VERSION 5.7 ;
  NOWIREEXTENSIONATPIN ON ;
  DIVIDERCHAR "/" ;
  BUSBITCHARS "[]" ;
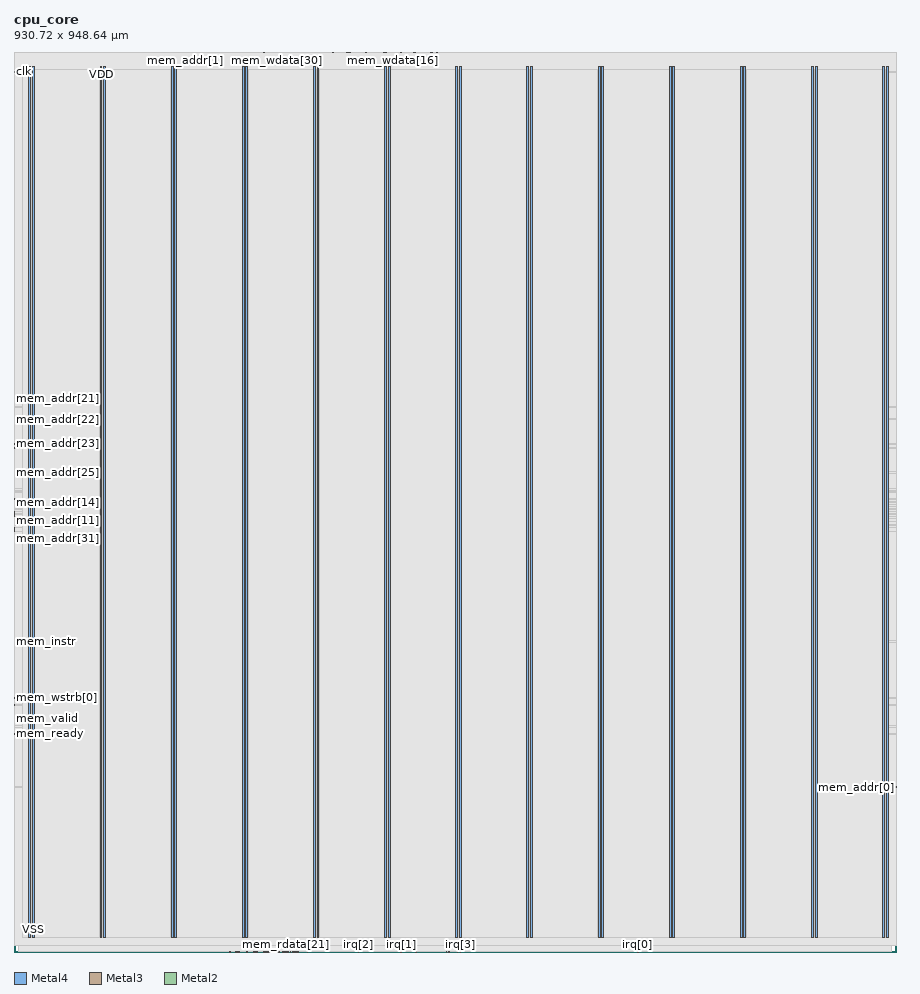
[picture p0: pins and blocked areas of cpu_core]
MACRO cpu_core
  CLASS BLOCK ;
  FOREIGN cpu_core ;
  ORIGIN 0.000 0.000 ;
  SIZE 930.720 BY 948.640 ;
  PIN VDD
    DIRECTION INOUT ;
    USE POWER ;
    PORT
      LAYER Metal4 ;
        RECT 15.720 15.380 17.720 933.260 ;
    END
    PORT
      LAYER Metal4 ;
        RECT 90.720 15.380 92.720 933.260 ;
    END
    PORT
      LAYER Metal4 ;
        RECT 165.720 15.380 167.720 933.260 ;
    END
    PORT
      LAYER Metal4 ;
        RECT 240.720 15.380 242.720 933.260 ;
    END
    PORT
      LAYER Metal4 ;
        RECT 315.720 15.380 317.720 933.260 ;
    END
    PORT
      LAYER Metal4 ;
        RECT 390.720 15.380 392.720 933.260 ;
    END
    PORT
      LAYER Metal4 ;
        RECT 465.720 15.380 467.720 933.260 ;
    END
    PORT
      LAYER Metal4 ;
        RECT 540.720 15.380 542.720 933.260 ;
    END
    PORT
      LAYER Metal4 ;
        RECT 615.720 15.380 617.720 933.260 ;
    END
    PORT
      LAYER Metal4 ;
        RECT 690.720 15.380 692.720 933.260 ;
    END
    PORT
      LAYER Metal4 ;
        RECT 765.720 15.380 767.720 933.260 ;
    END
    PORT
      LAYER Metal4 ;
        RECT 840.720 15.380 842.720 933.260 ;
    END
    PORT
      LAYER Metal4 ;
        RECT 915.720 15.380 917.720 933.260 ;
    END
  END VDD
  PIN VSS
    DIRECTION INOUT ;
    USE GROUND ;
    PORT
      LAYER Metal4 ;
        RECT 19.420 15.380 21.420 933.260 ;
    END
    PORT
      LAYER Metal4 ;
        RECT 94.420 15.380 96.420 933.260 ;
    END
    PORT
      LAYER Metal4 ;
        RECT 169.420 15.380 171.420 933.260 ;
    END
    PORT
      LAYER Metal4 ;
        RECT 244.420 15.380 246.420 933.260 ;
    END
    PORT
      LAYER Metal4 ;
        RECT 319.420 15.380 321.420 933.260 ;
    END
    PORT
      LAYER Metal4 ;
        RECT 394.420 15.380 396.420 933.260 ;
    END
    PORT
      LAYER Metal4 ;
        RECT 469.420 15.380 471.420 933.260 ;
    END
    PORT
      LAYER Metal4 ;
        RECT 544.420 15.380 546.420 933.260 ;
    END
    PORT
      LAYER Metal4 ;
        RECT 619.420 15.380 621.420 933.260 ;
    END
    PORT
      LAYER Metal4 ;
        RECT 694.420 15.380 696.420 933.260 ;
    END
    PORT
      LAYER Metal4 ;
        RECT 769.420 15.380 771.420 933.260 ;
    END
    PORT
      LAYER Metal4 ;
        RECT 844.420 15.380 846.420 933.260 ;
    END
    PORT
      LAYER Metal4 ;
        RECT 919.420 15.380 921.420 933.260 ;
    END
  END VSS
  PIN clk
    DIRECTION INPUT ;
    USE SIGNAL ;
    ANTENNAGATEAREA 4.738000 ;
    PORT
      LAYER Metal3 ;
        RECT 0.000 927.360 0.560 927.920 ;
    END
  END clk
  PIN irq[0]
    DIRECTION INPUT ;
    USE SIGNAL ;
    ANTENNAGATEAREA 0.498500 ;
    PORT
      LAYER Metal2 ;
        RECT 657.440 0.000 658.000 0.560 ;
    END
  END irq[0]
  PIN irq[1]
    DIRECTION INPUT ;
    USE SIGNAL ;
    ANTENNAGATEAREA 0.498500 ;
    PORT
      LAYER Metal2 ;
        RECT 407.680 0.000 408.240 0.560 ;
    END
  END irq[1]
  PIN irq[2]
    DIRECTION INPUT ;
    USE SIGNAL ;
    ANTENNAGATEAREA 0.498500 ;
    PORT
      LAYER Metal2 ;
        RECT 362.880 0.000 363.440 0.560 ;
    END
  END irq[2]
  PIN irq[3]
    DIRECTION INPUT ;
    USE SIGNAL ;
    ANTENNAGATEAREA 0.498500 ;
    PORT
      LAYER Metal2 ;
        RECT 470.400 0.000 470.960 0.560 ;
    END
  END irq[3]
  PIN irq[4]
    DIRECTION INPUT ;
    USE SIGNAL ;
    ANTENNAGATEAREA 0.498500 ;
    PORT
      LAYER Metal2 ;
        RECT 455.840 0.000 456.400 0.560 ;
    END
  END irq[4]
  PIN irq[5]
    DIRECTION INPUT ;
    USE SIGNAL ;
    ANTENNAGATEAREA 0.498500 ;
    PORT
      LAYER Metal2 ;
        RECT 458.080 0.000 458.640 0.560 ;
    END
  END irq[5]
  PIN irq[6]
    DIRECTION INPUT ;
    USE SIGNAL ;
    ANTENNAGATEAREA 0.498500 ;
    PORT
      LAYER Metal2 ;
        RECT 423.360 0.000 423.920 0.560 ;
    END
  END irq[6]
  PIN irq[7]
    DIRECTION INPUT ;
    USE SIGNAL ;
    ANTENNAGATEAREA 0.498500 ;
    PORT
      LAYER Metal2 ;
        RECT 467.040 0.000 467.600 0.560 ;
    END
  END irq[7]
  PIN mem_addr[0]
    DIRECTION OUTPUT ;
    USE SIGNAL ;
    ANTENNADIFFAREA 0.360800 ;
    PORT
      LAYER Metal3 ;
        RECT 930.160 173.600 930.720 174.160 ;
    END
  END mem_addr[0]
  PIN mem_addr[10]
    DIRECTION OUTPUT ;
    USE SIGNAL ;
    ANTENNADIFFAREA 1.986000 ;
    PORT
      LAYER Metal3 ;
        RECT 0.000 459.200 0.560 459.760 ;
    END
  END mem_addr[10]
  PIN mem_addr[11]
    DIRECTION OUTPUT ;
    USE SIGNAL ;
    ANTENNADIFFAREA 1.986000 ;
    PORT
      LAYER Metal3 ;
        RECT 0.000 454.720 0.560 455.280 ;
    END
  END mem_addr[11]
  PIN mem_addr[12]
    DIRECTION OUTPUT ;
    USE SIGNAL ;
    ANTENNADIFFAREA 1.986000 ;
    PORT
      LAYER Metal2 ;
        RECT 436.800 948.080 437.360 948.640 ;
    END
  END mem_addr[12]
  PIN mem_addr[13]
    DIRECTION OUTPUT ;
    USE SIGNAL ;
    ANTENNADIFFAREA 1.986000 ;
    PORT
      LAYER Metal2 ;
        RECT 432.320 948.080 432.880 948.640 ;
    END
  END mem_addr[13]
  PIN mem_addr[14]
    DIRECTION OUTPUT ;
    USE SIGNAL ;
    ANTENNADIFFAREA 1.986000 ;
    PORT
      LAYER Metal3 ;
        RECT 0.000 473.760 0.560 474.320 ;
    END
  END mem_addr[14]
  PIN mem_addr[15]
    DIRECTION OUTPUT ;
    USE SIGNAL ;
    ANTENNADIFFAREA 1.986000 ;
    PORT
      LAYER Metal2 ;
        RECT 416.640 948.080 417.200 948.640 ;
    END
  END mem_addr[15]
  PIN mem_addr[16]
    DIRECTION OUTPUT ;
    USE SIGNAL ;
    ANTENNADIFFAREA 1.986000 ;
    PORT
      LAYER Metal2 ;
        RECT 421.120 948.080 421.680 948.640 ;
    END
  END mem_addr[16]
  PIN mem_addr[17]
    DIRECTION OUTPUT ;
    USE SIGNAL ;
    ANTENNADIFFAREA 1.986000 ;
    PORT
      LAYER Metal2 ;
        RECT 407.680 948.080 408.240 948.640 ;
    END
  END mem_addr[17]
  PIN mem_addr[18]
    DIRECTION OUTPUT ;
    USE SIGNAL ;
    ANTENNADIFFAREA 1.986000 ;
    PORT
      LAYER Metal3 ;
        RECT 0.000 477.120 0.560 477.680 ;
    END
  END mem_addr[18]
  PIN mem_addr[19]
    DIRECTION OUTPUT ;
    USE SIGNAL ;
    ANTENNADIFFAREA 1.986000 ;
    PORT
      LAYER Metal2 ;
        RECT 440.160 948.080 440.720 948.640 ;
    END
  END mem_addr[19]
  PIN mem_addr[1]
    DIRECTION OUTPUT ;
    USE SIGNAL ;
    ANTENNADIFFAREA 0.360800 ;
    PORT
      LAYER Metal2 ;
        RECT 180.320 948.080 180.880 948.640 ;
    END
  END mem_addr[1]
  PIN mem_addr[20]
    DIRECTION OUTPUT ;
    USE SIGNAL ;
    ANTENNADIFFAREA 1.986000 ;
    PORT
      LAYER Metal2 ;
        RECT 417.760 948.080 418.320 948.640 ;
    END
  END mem_addr[20]
  PIN mem_addr[21]
    DIRECTION OUTPUT ;
    USE SIGNAL ;
    ANTENNADIFFAREA 1.986000 ;
    PORT
      LAYER Metal3 ;
        RECT 0.000 574.560 0.560 575.120 ;
    END
  END mem_addr[21]
  PIN mem_addr[22]
    DIRECTION OUTPUT ;
    USE SIGNAL ;
    ANTENNADIFFAREA 1.986000 ;
    PORT
      LAYER Metal3 ;
        RECT 0.000 561.120 0.560 561.680 ;
    END
  END mem_addr[22]
  PIN mem_addr[23]
    DIRECTION OUTPUT ;
    USE SIGNAL ;
    ANTENNADIFFAREA 1.986000 ;
    PORT
      LAYER Metal3 ;
        RECT 0.000 535.360 0.560 535.920 ;
    END
  END mem_addr[23]
  PIN mem_addr[24]
    DIRECTION OUTPUT ;
    USE SIGNAL ;
    ANTENNADIFFAREA 1.986000 ;
    PORT
      LAYER Metal3 ;
        RECT 0.000 530.880 0.560 531.440 ;
    END
  END mem_addr[24]
  PIN mem_addr[25]
    DIRECTION OUTPUT ;
    USE SIGNAL ;
    ANTENNADIFFAREA 1.986000 ;
    PORT
      LAYER Metal3 ;
        RECT 0.000 505.120 0.560 505.680 ;
    END
  END mem_addr[25]
  PIN mem_addr[26]
    DIRECTION OUTPUT ;
    USE SIGNAL ;
    ANTENNADIFFAREA 1.986000 ;
    PORT
      LAYER Metal3 ;
        RECT 0.000 484.960 0.560 485.520 ;
    END
  END mem_addr[26]
  PIN mem_addr[27]
    DIRECTION OUTPUT ;
    USE SIGNAL ;
    ANTENNADIFFAREA 1.986000 ;
    PORT
      LAYER Metal3 ;
        RECT 0.000 487.200 0.560 487.760 ;
    END
  END mem_addr[27]
  PIN mem_addr[28]
    DIRECTION OUTPUT ;
    USE SIGNAL ;
    ANTENNADIFFAREA 1.986000 ;
    PORT
      LAYER Metal3 ;
        RECT 0.000 463.680 0.560 464.240 ;
    END
  END mem_addr[28]
  PIN mem_addr[29]
    DIRECTION OUTPUT ;
    USE SIGNAL ;
    ANTENNADIFFAREA 1.986000 ;
    PORT
      LAYER Metal3 ;
        RECT 0.000 462.560 0.560 463.120 ;
    END
  END mem_addr[29]
  PIN mem_addr[2]
    DIRECTION OUTPUT ;
    USE SIGNAL ;
    ANTENNADIFFAREA 1.986000 ;
    PORT
      LAYER Metal3 ;
        RECT 0.000 467.040 0.560 467.600 ;
    END
  END mem_addr[2]
  PIN mem_addr[30]
    DIRECTION OUTPUT ;
    USE SIGNAL ;
    ANTENNADIFFAREA 1.986000 ;
    PORT
      LAYER Metal3 ;
        RECT 0.000 453.600 0.560 454.160 ;
    END
  END mem_addr[30]
  PIN mem_addr[31]
    DIRECTION OUTPUT ;
    USE SIGNAL ;
    ANTENNADIFFAREA 1.986000 ;
    PORT
      LAYER Metal3 ;
        RECT 0.000 443.520 0.560 444.080 ;
    END
  END mem_addr[31]
  PIN mem_addr[3]
    DIRECTION OUTPUT ;
    USE SIGNAL ;
    ANTENNADIFFAREA 1.986000 ;
    PORT
      LAYER Metal3 ;
        RECT 0.000 444.640 0.560 445.200 ;
    END
  END mem_addr[3]
  PIN mem_addr[4]
    DIRECTION OUTPUT ;
    USE SIGNAL ;
    ANTENNADIFFAREA 1.986000 ;
    PORT
      LAYER Metal3 ;
        RECT 0.000 460.320 0.560 460.880 ;
    END
  END mem_addr[4]
  PIN mem_addr[5]
    DIRECTION OUTPUT ;
    USE SIGNAL ;
    ANTENNADIFFAREA 1.986000 ;
    PORT
      LAYER Metal3 ;
        RECT 0.000 446.880 0.560 447.440 ;
    END
  END mem_addr[5]
  PIN mem_addr[6]
    DIRECTION OUTPUT ;
    USE SIGNAL ;
    ANTENNADIFFAREA 1.986000 ;
    PORT
      LAYER Metal3 ;
        RECT 0.000 470.400 0.560 470.960 ;
    END
  END mem_addr[6]
  PIN mem_addr[7]
    DIRECTION OUTPUT ;
    USE SIGNAL ;
    ANTENNADIFFAREA 1.986000 ;
    PORT
      LAYER Metal3 ;
        RECT 0.000 450.240 0.560 450.800 ;
    END
  END mem_addr[7]
  PIN mem_addr[8]
    DIRECTION OUTPUT ;
    USE SIGNAL ;
    ANTENNADIFFAREA 1.986000 ;
    PORT
      LAYER Metal3 ;
        RECT 0.000 455.840 0.560 456.400 ;
    END
  END mem_addr[8]
  PIN mem_addr[9]
    DIRECTION OUTPUT ;
    USE SIGNAL ;
    ANTENNADIFFAREA 1.986000 ;
    PORT
      LAYER Metal3 ;
        RECT 0.000 445.760 0.560 446.320 ;
    END
  END mem_addr[9]
  PIN mem_instr
    DIRECTION OUTPUT ;
    USE SIGNAL ;
    ANTENNADIFFAREA 1.986000 ;
    PORT
      LAYER Metal3 ;
        RECT 0.000 327.040 0.560 327.600 ;
    END
  END mem_instr
  PIN mem_rdata[0]
    DIRECTION INPUT ;
    USE SIGNAL ;
    ANTENNAGATEAREA 0.498500 ;
    PORT
      LAYER Metal2 ;
        RECT 235.200 0.000 235.760 0.560 ;
    END
  END mem_rdata[0]
  PIN mem_rdata[10]
    DIRECTION INPUT ;
    USE SIGNAL ;
    ANTENNAGATEAREA 0.498500 ;
    PORT
      LAYER Metal2 ;
        RECT 284.480 0.000 285.040 0.560 ;
    END
  END mem_rdata[10]
  PIN mem_rdata[11]
    DIRECTION INPUT ;
    USE SIGNAL ;
    ANTENNAGATEAREA 0.498500 ;
    PORT
      LAYER Metal2 ;
        RECT 285.600 0.000 286.160 0.560 ;
    END
  END mem_rdata[11]
  PIN mem_rdata[12]
    DIRECTION INPUT ;
    USE SIGNAL ;
    ANTENNAGATEAREA 0.498500 ;
    PORT
      LAYER Metal2 ;
        RECT 227.360 0.000 227.920 0.560 ;
    END
  END mem_rdata[12]
  PIN mem_rdata[13]
    DIRECTION INPUT ;
    USE SIGNAL ;
    ANTENNAGATEAREA 0.498500 ;
    PORT
      LAYER Metal2 ;
        RECT 253.120 0.000 253.680 0.560 ;
    END
  END mem_rdata[13]
  PIN mem_rdata[14]
    DIRECTION INPUT ;
    USE SIGNAL ;
    ANTENNAGATEAREA 0.498500 ;
    PORT
      LAYER Metal2 ;
        RECT 245.280 0.000 245.840 0.560 ;
    END
  END mem_rdata[14]
  PIN mem_rdata[15]
    DIRECTION INPUT ;
    USE SIGNAL ;
    ANTENNAGATEAREA 0.498500 ;
    PORT
      LAYER Metal2 ;
        RECT 283.360 0.000 283.920 0.560 ;
    END
  END mem_rdata[15]
  PIN mem_rdata[16]
    DIRECTION INPUT ;
    USE SIGNAL ;
    ANTENNAGATEAREA 0.498500 ;
    PORT
      LAYER Metal2 ;
        RECT 254.240 0.000 254.800 0.560 ;
    END
  END mem_rdata[16]
  PIN mem_rdata[17]
    DIRECTION INPUT ;
    USE SIGNAL ;
    ANTENNAGATEAREA 0.498500 ;
    PORT
      LAYER Metal2 ;
        RECT 274.400 0.000 274.960 0.560 ;
    END
  END mem_rdata[17]
  PIN mem_rdata[18]
    DIRECTION INPUT ;
    USE SIGNAL ;
    ANTENNAGATEAREA 0.498500 ;
    PORT
      LAYER Metal2 ;
        RECT 293.440 0.000 294.000 0.560 ;
    END
  END mem_rdata[18]
  PIN mem_rdata[19]
    DIRECTION INPUT ;
    USE SIGNAL ;
    ANTENNAGATEAREA 0.498500 ;
    PORT
      LAYER Metal2 ;
        RECT 263.200 0.000 263.760 0.560 ;
    END
  END mem_rdata[19]
  PIN mem_rdata[1]
    DIRECTION INPUT ;
    USE SIGNAL ;
    ANTENNAGATEAREA 0.498500 ;
    PORT
      LAYER Metal2 ;
        RECT 265.440 0.000 266.000 0.560 ;
    END
  END mem_rdata[1]
  PIN mem_rdata[20]
    DIRECTION INPUT ;
    USE SIGNAL ;
    ANTENNAGATEAREA 0.498500 ;
    PORT
      LAYER Metal2 ;
        RECT 276.640 0.000 277.200 0.560 ;
    END
  END mem_rdata[20]
  PIN mem_rdata[21]
    DIRECTION INPUT ;
    USE SIGNAL ;
    ANTENNAGATEAREA 0.498500 ;
    PORT
      LAYER Metal2 ;
        RECT 286.720 0.000 287.280 0.560 ;
    END
  END mem_rdata[21]
  PIN mem_rdata[22]
    DIRECTION INPUT ;
    USE SIGNAL ;
    ANTENNAGATEAREA 0.498500 ;
    PORT
      LAYER Metal2 ;
        RECT 275.520 0.000 276.080 0.560 ;
    END
  END mem_rdata[22]
  PIN mem_rdata[23]
    DIRECTION INPUT ;
    USE SIGNAL ;
    ANTENNAGATEAREA 0.498500 ;
    PORT
      LAYER Metal2 ;
        RECT 294.560 0.000 295.120 0.560 ;
    END
  END mem_rdata[23]
  PIN mem_rdata[24]
    DIRECTION INPUT ;
    USE SIGNAL ;
    ANTENNAGATEAREA 0.498500 ;
    PORT
      LAYER Metal2 ;
        RECT 299.040 0.000 299.600 0.560 ;
    END
  END mem_rdata[24]
  PIN mem_rdata[25]
    DIRECTION INPUT ;
    USE SIGNAL ;
    ANTENNAGATEAREA 0.498500 ;
    PORT
      LAYER Metal2 ;
        RECT 295.680 0.000 296.240 0.560 ;
    END
  END mem_rdata[25]
  PIN mem_rdata[26]
    DIRECTION INPUT ;
    USE SIGNAL ;
    ANTENNAGATEAREA 0.498500 ;
    PORT
      LAYER Metal2 ;
        RECT 273.280 0.000 273.840 0.560 ;
    END
  END mem_rdata[26]
  PIN mem_rdata[27]
    DIRECTION INPUT ;
    USE SIGNAL ;
    ANTENNAGATEAREA 0.498500 ;
    PORT
      LAYER Metal2 ;
        RECT 236.320 0.000 236.880 0.560 ;
    END
  END mem_rdata[27]
  PIN mem_rdata[28]
    DIRECTION INPUT ;
    USE SIGNAL ;
    ANTENNAGATEAREA 0.498500 ;
    PORT
      LAYER Metal2 ;
        RECT 232.960 0.000 233.520 0.560 ;
    END
  END mem_rdata[28]
  PIN mem_rdata[29]
    DIRECTION INPUT ;
    USE SIGNAL ;
    ANTENNAGATEAREA 0.498500 ;
    PORT
      LAYER Metal2 ;
        RECT 255.360 0.000 255.920 0.560 ;
    END
  END mem_rdata[29]
  PIN mem_rdata[2]
    DIRECTION INPUT ;
    USE SIGNAL ;
    ANTENNAGATEAREA 0.498500 ;
    PORT
      LAYER Metal2 ;
        RECT 287.840 0.000 288.400 0.560 ;
    END
  END mem_rdata[2]
  PIN mem_rdata[30]
    DIRECTION INPUT ;
    USE SIGNAL ;
    ANTENNAGATEAREA 0.498500 ;
    PORT
      LAYER Metal2 ;
        RECT 234.080 0.000 234.640 0.560 ;
    END
  END mem_rdata[30]
  PIN mem_rdata[31]
    DIRECTION INPUT ;
    USE SIGNAL ;
    ANTENNAGATEAREA 0.498500 ;
    PORT
      LAYER Metal2 ;
        RECT 237.440 0.000 238.000 0.560 ;
    END
  END mem_rdata[31]
  PIN mem_rdata[3]
    DIRECTION INPUT ;
    USE SIGNAL ;
    ANTENNAGATEAREA 0.498500 ;
    PORT
      LAYER Metal2 ;
        RECT 264.320 0.000 264.880 0.560 ;
    END
  END mem_rdata[3]
  PIN mem_rdata[4]
    DIRECTION INPUT ;
    USE SIGNAL ;
    ANTENNAGATEAREA 0.498500 ;
    PORT
      LAYER Metal2 ;
        RECT 266.560 0.000 267.120 0.560 ;
    END
  END mem_rdata[4]
  PIN mem_rdata[5]
    DIRECTION INPUT ;
    USE SIGNAL ;
    ANTENNAGATEAREA 0.498500 ;
    PORT
      LAYER Metal2 ;
        RECT 291.200 0.000 291.760 0.560 ;
    END
  END mem_rdata[5]
  PIN mem_rdata[6]
    DIRECTION INPUT ;
    USE SIGNAL ;
    ANTENNAGATEAREA 0.498500 ;
    PORT
      LAYER Metal2 ;
        RECT 267.680 0.000 268.240 0.560 ;
    END
  END mem_rdata[6]
  PIN mem_rdata[7]
    DIRECTION INPUT ;
    USE SIGNAL ;
    ANTENNAGATEAREA 0.498500 ;
    PORT
      LAYER Metal2 ;
        RECT 288.960 0.000 289.520 0.560 ;
    END
  END mem_rdata[7]
  PIN mem_rdata[8]
    DIRECTION INPUT ;
    USE SIGNAL ;
    ANTENNAGATEAREA 0.498500 ;
    PORT
      LAYER Metal2 ;
        RECT 296.800 0.000 297.360 0.560 ;
    END
  END mem_rdata[8]
  PIN mem_rdata[9]
    DIRECTION INPUT ;
    USE SIGNAL ;
    ANTENNAGATEAREA 0.498500 ;
    PORT
      LAYER Metal2 ;
        RECT 278.880 0.000 279.440 0.560 ;
    END
  END mem_rdata[9]
  PIN mem_ready
    DIRECTION INPUT ;
    USE SIGNAL ;
    ANTENNAGATEAREA 0.498500 ;
    PORT
      LAYER Metal3 ;
        RECT 0.000 229.600 0.560 230.160 ;
    END
  END mem_ready
  PIN mem_valid
    DIRECTION OUTPUT ;
    USE SIGNAL ;
    ANTENNADIFFAREA 1.986000 ;
    PORT
      LAYER Metal3 ;
        RECT 0.000 237.440 0.560 238.000 ;
    END
  END mem_valid
  PIN mem_wdata[0]
    DIRECTION OUTPUT ;
    USE SIGNAL ;
    ANTENNADIFFAREA 1.986000 ;
    PORT
      LAYER Metal2 ;
        RECT 439.040 948.080 439.600 948.640 ;
    END
  END mem_wdata[0]
  PIN mem_wdata[10]
    DIRECTION OUTPUT ;
    USE SIGNAL ;
    ANTENNADIFFAREA 1.986000 ;
    PORT
      LAYER Metal2 ;
        RECT 361.760 948.080 362.320 948.640 ;
    END
  END mem_wdata[10]
  PIN mem_wdata[11]
    DIRECTION OUTPUT ;
    USE SIGNAL ;
    ANTENNADIFFAREA 1.986000 ;
    PORT
      LAYER Metal2 ;
        RECT 392.000 948.080 392.560 948.640 ;
    END
  END mem_wdata[11]
  PIN mem_wdata[12]
    DIRECTION OUTPUT ;
    USE SIGNAL ;
    ANTENNADIFFAREA 1.986000 ;
    PORT
      LAYER Metal2 ;
        RECT 366.240 948.080 366.800 948.640 ;
    END
  END mem_wdata[12]
  PIN mem_wdata[13]
    DIRECTION OUTPUT ;
    USE SIGNAL ;
    ANTENNADIFFAREA 1.986000 ;
    PORT
      LAYER Metal2 ;
        RECT 390.880 948.080 391.440 948.640 ;
    END
  END mem_wdata[13]
  PIN mem_wdata[14]
    DIRECTION OUTPUT ;
    USE SIGNAL ;
    ANTENNADIFFAREA 1.986000 ;
    PORT
      LAYER Metal2 ;
        RECT 360.640 948.080 361.200 948.640 ;
    END
  END mem_wdata[14]
  PIN mem_wdata[15]
    DIRECTION OUTPUT ;
    USE SIGNAL ;
    ANTENNADIFFAREA 1.986000 ;
    PORT
      LAYER Metal2 ;
        RECT 389.760 948.080 390.320 948.640 ;
    END
  END mem_wdata[15]
  PIN mem_wdata[16]
    DIRECTION OUTPUT ;
    USE SIGNAL ;
    ANTENNADIFFAREA 1.986000 ;
    PORT
      LAYER Metal2 ;
        RECT 398.720 948.080 399.280 948.640 ;
    END
  END mem_wdata[16]
  PIN mem_wdata[17]
    DIRECTION OUTPUT ;
    USE SIGNAL ;
    ANTENNADIFFAREA 1.986000 ;
    PORT
      LAYER Metal2 ;
        RECT 412.160 948.080 412.720 948.640 ;
    END
  END mem_wdata[17]
  PIN mem_wdata[18]
    DIRECTION OUTPUT ;
    USE SIGNAL ;
    ANTENNADIFFAREA 1.986000 ;
    PORT
      LAYER Metal2 ;
        RECT 422.240 948.080 422.800 948.640 ;
    END
  END mem_wdata[18]
  PIN mem_wdata[19]
    DIRECTION OUTPUT ;
    USE SIGNAL ;
    ANTENNADIFFAREA 1.986000 ;
    PORT
      LAYER Metal2 ;
        RECT 415.520 948.080 416.080 948.640 ;
    END
  END mem_wdata[19]
  PIN mem_wdata[1]
    DIRECTION OUTPUT ;
    USE SIGNAL ;
    ANTENNADIFFAREA 1.986000 ;
    PORT
      LAYER Metal2 ;
        RECT 431.200 948.080 431.760 948.640 ;
    END
  END mem_wdata[1]
  PIN mem_wdata[20]
    DIRECTION OUTPUT ;
    USE SIGNAL ;
    ANTENNADIFFAREA 1.986000 ;
    PORT
      LAYER Metal2 ;
        RECT 370.720 948.080 371.280 948.640 ;
    END
  END mem_wdata[20]
  PIN mem_wdata[21]
    DIRECTION OUTPUT ;
    USE SIGNAL ;
    ANTENNADIFFAREA 1.986000 ;
    PORT
      LAYER Metal2 ;
        RECT 400.960 948.080 401.520 948.640 ;
    END
  END mem_wdata[21]
  PIN mem_wdata[22]
    DIRECTION OUTPUT ;
    USE SIGNAL ;
    ANTENNADIFFAREA 1.986000 ;
    PORT
      LAYER Metal2 ;
        RECT 351.680 948.080 352.240 948.640 ;
    END
  END mem_wdata[22]
  PIN mem_wdata[23]
    DIRECTION OUTPUT ;
    USE SIGNAL ;
    ANTENNADIFFAREA 1.986000 ;
    PORT
      LAYER Metal2 ;
        RECT 353.920 948.080 354.480 948.640 ;
    END
  END mem_wdata[23]
  PIN mem_wdata[24]
    DIRECTION OUTPUT ;
    USE SIGNAL ;
    ANTENNADIFFAREA 1.986000 ;
    PORT
      LAYER Metal2 ;
        RECT 350.560 948.080 351.120 948.640 ;
    END
  END mem_wdata[24]
  PIN mem_wdata[25]
    DIRECTION OUTPUT ;
    USE SIGNAL ;
    ANTENNADIFFAREA 1.986000 ;
    PORT
      LAYER Metal2 ;
        RECT 336.000 948.080 336.560 948.640 ;
    END
  END mem_wdata[25]
  PIN mem_wdata[26]
    DIRECTION OUTPUT ;
    USE SIGNAL ;
    ANTENNADIFFAREA 1.986000 ;
    PORT
      LAYER Metal2 ;
        RECT 305.760 948.080 306.320 948.640 ;
    END
  END mem_wdata[26]
  PIN mem_wdata[27]
    DIRECTION OUTPUT ;
    USE SIGNAL ;
    ANTENNADIFFAREA 1.986000 ;
    PORT
      LAYER Metal2 ;
        RECT 253.120 948.080 253.680 948.640 ;
    END
  END mem_wdata[27]
  PIN mem_wdata[28]
    DIRECTION OUTPUT ;
    USE SIGNAL ;
    ANTENNADIFFAREA 1.986000 ;
    PORT
      LAYER Metal2 ;
        RECT 256.480 948.080 257.040 948.640 ;
    END
  END mem_wdata[28]
  PIN mem_wdata[29]
    DIRECTION OUTPUT ;
    USE SIGNAL ;
    ANTENNADIFFAREA 1.986000 ;
    PORT
      LAYER Metal2 ;
        RECT 263.200 948.080 263.760 948.640 ;
    END
  END mem_wdata[29]
  PIN mem_wdata[2]
    DIRECTION OUTPUT ;
    USE SIGNAL ;
    ANTENNADIFFAREA 1.986000 ;
    PORT
      LAYER Metal2 ;
        RECT 445.760 948.080 446.320 948.640 ;
    END
  END mem_wdata[2]
  PIN mem_wdata[30]
    DIRECTION OUTPUT ;
    USE SIGNAL ;
    ANTENNADIFFAREA 1.986000 ;
    PORT
      LAYER Metal2 ;
        RECT 276.640 948.080 277.200 948.640 ;
    END
  END mem_wdata[30]
  PIN mem_wdata[31]
    DIRECTION OUTPUT ;
    USE SIGNAL ;
    ANTENNADIFFAREA 1.986000 ;
    PORT
      LAYER Metal2 ;
        RECT 252.000 948.080 252.560 948.640 ;
    END
  END mem_wdata[31]
  PIN mem_wdata[3]
    DIRECTION OUTPUT ;
    USE SIGNAL ;
    ANTENNADIFFAREA 1.986000 ;
    PORT
      LAYER Metal2 ;
        RECT 449.120 948.080 449.680 948.640 ;
    END
  END mem_wdata[3]
  PIN mem_wdata[4]
    DIRECTION OUTPUT ;
    USE SIGNAL ;
    ANTENNADIFFAREA 1.986000 ;
    PORT
      LAYER Metal2 ;
        RECT 433.440 948.080 434.000 948.640 ;
    END
  END mem_wdata[4]
  PIN mem_wdata[5]
    DIRECTION OUTPUT ;
    USE SIGNAL ;
    ANTENNADIFFAREA 1.986000 ;
    PORT
      LAYER Metal2 ;
        RECT 455.840 948.080 456.400 948.640 ;
    END
  END mem_wdata[5]
  PIN mem_wdata[6]
    DIRECTION OUTPUT ;
    USE SIGNAL ;
    ANTENNADIFFAREA 1.986000 ;
    PORT
      LAYER Metal2 ;
        RECT 383.040 948.080 383.600 948.640 ;
    END
  END mem_wdata[6]
  PIN mem_wdata[7]
    DIRECTION OUTPUT ;
    USE SIGNAL ;
    ANTENNADIFFAREA 1.986000 ;
    PORT
      LAYER Metal2 ;
        RECT 379.680 948.080 380.240 948.640 ;
    END
  END mem_wdata[7]
  PIN mem_wdata[8]
    DIRECTION OUTPUT ;
    USE SIGNAL ;
    ANTENNADIFFAREA 1.986000 ;
    PORT
      LAYER Metal2 ;
        RECT 348.320 948.080 348.880 948.640 ;
    END
  END mem_wdata[8]
  PIN mem_wdata[9]
    DIRECTION OUTPUT ;
    USE SIGNAL ;
    ANTENNADIFFAREA 1.986000 ;
    PORT
      LAYER Metal2 ;
        RECT 376.320 948.080 376.880 948.640 ;
    END
  END mem_wdata[9]
  PIN mem_wstrb[0]
    DIRECTION OUTPUT ;
    USE SIGNAL ;
    ANTENNADIFFAREA 1.986000 ;
    PORT
      LAYER Metal3 ;
        RECT 0.000 259.840 0.560 260.400 ;
    END
  END mem_wstrb[0]
  PIN mem_wstrb[1]
    DIRECTION OUTPUT ;
    USE SIGNAL ;
    ANTENNADIFFAREA 1.986000 ;
    PORT
      LAYER Metal2 ;
        RECT 252.000 0.000 252.560 0.560 ;
    END
  END mem_wstrb[1]
  PIN mem_wstrb[2]
    DIRECTION OUTPUT ;
    USE SIGNAL ;
    ANTENNADIFFAREA 1.986000 ;
    PORT
      LAYER Metal2 ;
        RECT 256.480 0.000 257.040 0.560 ;
    END
  END mem_wstrb[2]
  PIN mem_wstrb[3]
    DIRECTION OUTPUT ;
    USE SIGNAL ;
    ANTENNADIFFAREA 1.986000 ;
    PORT
      LAYER Metal3 ;
        RECT 0.000 267.680 0.560 268.240 ;
    END
  END mem_wstrb[3]
  PIN resetn
    DIRECTION INPUT ;
    USE SIGNAL ;
    ANTENNAGATEAREA 0.498500 ;
    PORT
      LAYER Metal2 ;
        RECT 309.120 0.000 309.680 0.560 ;
    END
  END resetn
  OBS
      LAYER Nwell ;
        RECT 6.290 15.250 924.430 933.390 ;
      LAYER Metal1 ;
        RECT 6.720 15.380 924.000 933.260 ;
      LAYER Metal2 ;
        RECT 5.180 947.780 180.020 948.500 ;
        RECT 181.180 947.780 251.700 948.500 ;
        RECT 253.980 947.780 256.180 948.500 ;
        RECT 257.340 947.780 262.900 948.500 ;
        RECT 264.060 947.780 276.340 948.500 ;
        RECT 277.500 947.780 305.460 948.500 ;
        RECT 306.620 947.780 335.700 948.500 ;
        RECT 336.860 947.780 348.020 948.500 ;
        RECT 349.180 947.780 350.260 948.500 ;
        RECT 352.540 947.780 353.620 948.500 ;
        RECT 354.780 947.780 360.340 948.500 ;
        RECT 362.620 947.780 365.940 948.500 ;
        RECT 367.100 947.780 370.420 948.500 ;
        RECT 371.580 947.780 376.020 948.500 ;
        RECT 377.180 947.780 379.380 948.500 ;
        RECT 380.540 947.780 382.740 948.500 ;
        RECT 383.900 947.780 389.460 948.500 ;
        RECT 392.860 947.780 398.420 948.500 ;
        RECT 399.580 947.780 400.660 948.500 ;
        RECT 401.820 947.780 407.380 948.500 ;
        RECT 408.540 947.780 411.860 948.500 ;
        RECT 413.020 947.780 415.220 948.500 ;
        RECT 418.620 947.780 420.820 948.500 ;
        RECT 423.100 947.780 430.900 948.500 ;
        RECT 434.300 947.780 436.500 948.500 ;
        RECT 437.660 947.780 438.740 948.500 ;
        RECT 441.020 947.780 445.460 948.500 ;
        RECT 446.620 947.780 448.820 948.500 ;
        RECT 449.980 947.780 455.540 948.500 ;
        RECT 456.700 947.780 924.420 948.500 ;
        RECT 5.180 0.860 924.420 947.780 ;
        RECT 5.180 0.140 227.060 0.860 ;
        RECT 228.220 0.140 232.660 0.860 ;
        RECT 238.300 0.140 244.980 0.860 ;
        RECT 246.140 0.140 251.700 0.860 ;
        RECT 257.340 0.140 262.900 0.860 ;
        RECT 268.540 0.140 272.980 0.860 ;
        RECT 277.500 0.140 278.580 0.860 ;
        RECT 279.740 0.140 283.060 0.860 ;
        RECT 289.820 0.140 290.900 0.860 ;
        RECT 292.060 0.140 293.140 0.860 ;
        RECT 297.660 0.140 298.740 0.860 ;
        RECT 299.900 0.140 308.820 0.860 ;
        RECT 309.980 0.140 362.580 0.860 ;
        RECT 363.740 0.140 407.380 0.860 ;
        RECT 408.540 0.140 423.060 0.860 ;
        RECT 424.220 0.140 455.540 0.860 ;
        RECT 456.700 0.140 457.780 0.860 ;
        RECT 458.940 0.140 466.740 0.860 ;
        RECT 467.900 0.140 470.100 0.860 ;
        RECT 471.260 0.140 657.140 0.860 ;
        RECT 658.300 0.140 924.420 0.860 ;
      LAYER Metal3 ;
        RECT 0.560 928.220 930.160 947.940 ;
        RECT 0.860 927.060 930.160 928.220 ;
        RECT 0.560 575.420 930.160 927.060 ;
        RECT 0.860 574.260 930.160 575.420 ;
        RECT 0.560 561.980 930.160 574.260 ;
        RECT 0.860 560.820 930.160 561.980 ;
        RECT 0.560 536.220 930.160 560.820 ;
        RECT 0.860 535.060 930.160 536.220 ;
        RECT 0.560 531.740 930.160 535.060 ;
        RECT 0.860 530.580 930.160 531.740 ;
        RECT 0.560 505.980 930.160 530.580 ;
        RECT 0.860 504.820 930.160 505.980 ;
        RECT 0.560 488.060 930.160 504.820 ;
        RECT 0.860 486.900 930.160 488.060 ;
        RECT 0.560 485.820 930.160 486.900 ;
        RECT 0.860 484.660 930.160 485.820 ;
        RECT 0.560 477.980 930.160 484.660 ;
        RECT 0.860 476.820 930.160 477.980 ;
        RECT 0.560 474.620 930.160 476.820 ;
        RECT 0.860 473.460 930.160 474.620 ;
        RECT 0.560 471.260 930.160 473.460 ;
        RECT 0.860 470.100 930.160 471.260 ;
        RECT 0.560 467.900 930.160 470.100 ;
        RECT 0.860 466.740 930.160 467.900 ;
        RECT 0.560 464.540 930.160 466.740 ;
        RECT 0.860 462.260 930.160 464.540 ;
        RECT 0.560 461.180 930.160 462.260 ;
        RECT 0.860 458.900 930.160 461.180 ;
        RECT 0.560 456.700 930.160 458.900 ;
        RECT 0.860 453.300 930.160 456.700 ;
        RECT 0.560 451.100 930.160 453.300 ;
        RECT 0.860 449.940 930.160 451.100 ;
        RECT 0.560 447.740 930.160 449.940 ;
        RECT 0.860 443.220 930.160 447.740 ;
        RECT 0.560 327.900 930.160 443.220 ;
        RECT 0.860 326.740 930.160 327.900 ;
        RECT 0.560 268.540 930.160 326.740 ;
        RECT 0.860 267.380 930.160 268.540 ;
        RECT 0.560 260.700 930.160 267.380 ;
        RECT 0.860 259.540 930.160 260.700 ;
        RECT 0.560 238.300 930.160 259.540 ;
        RECT 0.860 237.140 930.160 238.300 ;
        RECT 0.560 230.460 930.160 237.140 ;
        RECT 0.860 229.300 930.160 230.460 ;
        RECT 0.560 174.460 930.160 229.300 ;
        RECT 0.560 173.300 929.860 174.460 ;
        RECT 0.560 6.860 930.160 173.300 ;
      LAYER Metal4 ;
        RECT 8.540 15.770 15.420 930.630 ;
        RECT 18.020 15.770 19.120 930.630 ;
        RECT 21.720 15.770 90.420 930.630 ;
        RECT 93.020 15.770 94.120 930.630 ;
        RECT 96.720 15.770 165.420 930.630 ;
        RECT 168.020 15.770 169.120 930.630 ;
        RECT 171.720 15.770 240.420 930.630 ;
        RECT 243.020 15.770 244.120 930.630 ;
        RECT 246.720 15.770 315.420 930.630 ;
        RECT 318.020 15.770 319.120 930.630 ;
        RECT 321.720 15.770 390.420 930.630 ;
        RECT 393.020 15.770 394.120 930.630 ;
        RECT 396.720 15.770 465.420 930.630 ;
        RECT 468.020 15.770 469.120 930.630 ;
        RECT 471.720 15.770 540.420 930.630 ;
        RECT 543.020 15.770 544.120 930.630 ;
        RECT 546.720 15.770 615.420 930.630 ;
        RECT 618.020 15.770 619.120 930.630 ;
        RECT 621.720 15.770 690.420 930.630 ;
        RECT 693.020 15.770 694.120 930.630 ;
        RECT 696.720 15.770 765.420 930.630 ;
        RECT 768.020 15.770 769.120 930.630 ;
        RECT 771.720 15.770 840.420 930.630 ;
        RECT 843.020 15.770 844.120 930.630 ;
        RECT 846.720 15.770 915.420 930.630 ;
        RECT 918.020 15.770 919.120 930.630 ;
        RECT 921.720 15.770 922.180 930.630 ;
  END
END cpu_core
END LIBRARY

